VERSION 5.7 ;
  NOWIREEXTENSIONATPIN ON ;
  DIVIDERCHAR "/" ;
  BUSBITCHARS "[]" ;
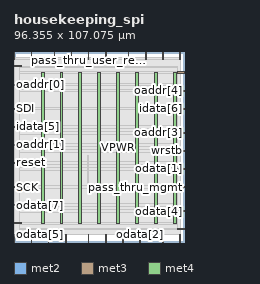
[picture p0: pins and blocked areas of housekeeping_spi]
MACRO housekeeping_spi
  CLASS BLOCK ;
  FOREIGN housekeeping_spi ;
  ORIGIN 0.000 0.000 ;
  SIZE 96.355 BY 107.075 ;
  PIN CSB
    DIRECTION INPUT ;
    USE SIGNAL ;
    ANTENNAGATEAREA 0.196500 ;
    PORT
      LAYER met2 ;
        RECT 51.610 0.000 51.890 4.000 ;
    END
  END CSB
  PIN SCK
    DIRECTION INPUT ;
    USE SIGNAL ;
    ANTENNAGATEAREA 0.852000 ;
    PORT
      LAYER met3 ;
        RECT 0.000 30.640 4.000 31.240 ;
    END
  END SCK
  PIN SDI
    DIRECTION INPUT ;
    USE SIGNAL ;
    ANTENNAGATEAREA 0.159000 ;
    PORT
      LAYER met3 ;
        RECT 0.000 74.840 4.000 75.440 ;
    END
  END SDI
  PIN SDO
    DIRECTION OUTPUT TRISTATE ;
    USE SIGNAL ;
    ANTENNADIFFAREA 0.795200 ;
    PORT
      LAYER met2 ;
        RECT 74.150 103.075 74.430 107.075 ;
    END
  END SDO
  PIN VGND
    DIRECTION INOUT ;
    USE GROUND ;
    PORT
      LAYER met4 ;
        RECT 25.990 10.640 27.590 95.440 ;
    END
    PORT
      LAYER met4 ;
        RECT 47.265 10.640 48.865 95.440 ;
    END
    PORT
      LAYER met4 ;
        RECT 68.540 10.640 70.140 95.440 ;
    END
    PORT
      LAYER met4 ;
        RECT 89.815 10.640 91.415 95.440 ;
    END
  END VGND
  PIN VPWR
    DIRECTION INOUT ;
    USE POWER ;
    PORT
      LAYER met4 ;
        RECT 15.355 10.640 16.955 95.440 ;
    END
    PORT
      LAYER met4 ;
        RECT 36.630 10.640 38.230 95.440 ;
    END
    PORT
      LAYER met4 ;
        RECT 57.905 10.640 59.505 95.440 ;
    END
    PORT
      LAYER met4 ;
        RECT 79.180 10.640 80.780 95.440 ;
    END
  END VPWR
  PIN idata[0]
    DIRECTION INPUT ;
    USE SIGNAL ;
    ANTENNAGATEAREA 0.196500 ;
    PORT
      LAYER met2 ;
        RECT 51.610 103.075 51.890 107.075 ;
    END
  END idata[0]
  PIN idata[1]
    DIRECTION INPUT ;
    USE SIGNAL ;
    ANTENNAGATEAREA 0.196500 ;
    PORT
      LAYER met2 ;
        RECT 64.490 103.075 64.770 107.075 ;
    END
  END idata[1]
  PIN idata[2]
    DIRECTION INPUT ;
    USE SIGNAL ;
    ANTENNAGATEAREA 0.196500 ;
    PORT
      LAYER met2 ;
        RECT 9.750 103.075 10.030 107.075 ;
    END
  END idata[2]
  PIN idata[3]
    DIRECTION INPUT ;
    USE SIGNAL ;
    ANTENNAGATEAREA 0.196500 ;
    PORT
      LAYER met2 ;
        RECT 93.470 0.000 93.750 4.000 ;
    END
  END idata[3]
  PIN idata[4]
    DIRECTION INPUT ;
    USE SIGNAL ;
    ANTENNAGATEAREA 0.196500 ;
    PORT
      LAYER met2 ;
        RECT 83.810 0.000 84.090 4.000 ;
    END
  END idata[4]
  PIN idata[5]
    DIRECTION INPUT ;
    USE SIGNAL ;
    ANTENNAGATEAREA 0.196500 ;
    PORT
      LAYER met3 ;
        RECT 0.000 64.640 4.000 65.240 ;
    END
  END idata[5]
  PIN idata[6]
    DIRECTION INPUT ;
    USE SIGNAL ;
    ANTENNAGATEAREA 0.196500 ;
    PORT
      LAYER met3 ;
        RECT 92.355 74.840 96.355 75.440 ;
    END
  END idata[6]
  PIN idata[7]
    DIRECTION INPUT ;
    USE SIGNAL ;
    ANTENNAGATEAREA 0.196500 ;
    PORT
      LAYER met2 ;
        RECT 22.630 103.075 22.910 107.075 ;
    END
  END idata[7]
  PIN oaddr[0]
    DIRECTION OUTPUT TRISTATE ;
    USE SIGNAL ;
    ANTENNADIFFAREA 0.795200 ;
    PORT
      LAYER met3 ;
        RECT 0.000 88.440 4.000 89.040 ;
    END
  END oaddr[0]
  PIN oaddr[1]
    DIRECTION OUTPUT TRISTATE ;
    USE SIGNAL ;
    ANTENNADIFFAREA 0.795200 ;
    PORT
      LAYER met3 ;
        RECT 0.000 54.440 4.000 55.040 ;
    END
  END oaddr[1]
  PIN oaddr[2]
    DIRECTION OUTPUT TRISTATE ;
    USE SIGNAL ;
    ANTENNADIFFAREA 0.795200 ;
    PORT
      LAYER met3 ;
        RECT 92.355 6.840 96.355 7.440 ;
    END
  END oaddr[2]
  PIN oaddr[3]
    DIRECTION OUTPUT TRISTATE ;
    USE SIGNAL ;
    ANTENNADIFFAREA 0.795200 ;
    PORT
      LAYER met3 ;
        RECT 92.355 61.240 96.355 61.840 ;
    END
  END oaddr[3]
  PIN oaddr[4]
    DIRECTION OUTPUT TRISTATE ;
    USE SIGNAL ;
    ANTENNADIFFAREA 0.445500 ;
    PORT
      LAYER met3 ;
        RECT 92.355 85.040 96.355 85.640 ;
    END
  END oaddr[4]
  PIN oaddr[5]
    DIRECTION OUTPUT TRISTATE ;
    USE SIGNAL ;
    ANTENNADIFFAREA 0.795200 ;
    PORT
      LAYER met2 ;
        RECT 0.090 0.000 0.370 4.000 ;
    END
  END oaddr[5]
  PIN oaddr[6]
    DIRECTION OUTPUT TRISTATE ;
    USE SIGNAL ;
    ANTENNADIFFAREA 0.795200 ;
    PORT
      LAYER met2 ;
        RECT 0.090 103.075 0.370 107.075 ;
    END
  END oaddr[6]
  PIN oaddr[7]
    DIRECTION OUTPUT TRISTATE ;
    USE SIGNAL ;
    ANTENNADIFFAREA 0.795200 ;
    PORT
      LAYER met3 ;
        RECT 0.000 10.240 4.000 10.840 ;
    END
  END oaddr[7]
  PIN odata[0]
    DIRECTION OUTPUT TRISTATE ;
    USE SIGNAL ;
    ANTENNADIFFAREA 0.795200 ;
    PORT
      LAYER met2 ;
        RECT 29.070 0.000 29.350 4.000 ;
    END
  END odata[0]
  PIN odata[1]
    DIRECTION OUTPUT TRISTATE ;
    USE SIGNAL ;
    ANTENNADIFFAREA 0.795200 ;
    PORT
      LAYER met3 ;
        RECT 92.355 40.840 96.355 41.440 ;
    END
  END odata[1]
  PIN odata[2]
    DIRECTION OUTPUT TRISTATE ;
    USE SIGNAL ;
    ANTENNADIFFAREA 0.795200 ;
    PORT
      LAYER met2 ;
        RECT 70.930 0.000 71.210 4.000 ;
    END
  END odata[2]
  PIN odata[3]
    DIRECTION OUTPUT TRISTATE ;
    USE SIGNAL ;
    ANTENNADIFFAREA 0.795200 ;
    PORT
      LAYER met2 ;
        RECT 83.810 103.075 84.090 107.075 ;
    END
  END odata[3]
  PIN odata[4]
    DIRECTION OUTPUT TRISTATE ;
    USE SIGNAL ;
    ANTENNADIFFAREA 0.445500 ;
    PORT
      LAYER met3 ;
        RECT 92.355 17.040 96.355 17.640 ;
    END
  END odata[4]
  PIN odata[5]
    DIRECTION OUTPUT TRISTATE ;
    USE SIGNAL ;
    ANTENNADIFFAREA 0.795200 ;
    PORT
      LAYER met2 ;
        RECT 9.750 0.000 10.030 4.000 ;
    END
  END odata[5]
  PIN odata[6]
    DIRECTION OUTPUT TRISTATE ;
    USE SIGNAL ;
    ANTENNADIFFAREA 0.795200 ;
    PORT
      LAYER met2 ;
        RECT 19.410 0.000 19.690 4.000 ;
    END
  END odata[6]
  PIN odata[7]
    DIRECTION OUTPUT TRISTATE ;
    USE SIGNAL ;
    ANTENNADIFFAREA 0.795200 ;
    PORT
      LAYER met3 ;
        RECT 0.000 20.440 4.000 21.040 ;
    END
  END odata[7]
  PIN pass_thru_mgmt
    DIRECTION OUTPUT TRISTATE ;
    USE SIGNAL ;
    ANTENNADIFFAREA 0.445500 ;
    PORT
      LAYER met3 ;
        RECT 92.355 30.640 96.355 31.240 ;
    END
  END pass_thru_mgmt
  PIN pass_thru_mgmt_delay
    DIRECTION OUTPUT TRISTATE ;
    USE SIGNAL ;
    ANTENNADIFFAREA 0.795200 ;
    PORT
      LAYER met2 ;
        RECT 41.950 0.000 42.230 4.000 ;
    END
  END pass_thru_mgmt_delay
  PIN pass_thru_mgmt_reset
    DIRECTION OUTPUT TRISTATE ;
    USE SIGNAL ;
    ANTENNADIFFAREA 0.445500 ;
    PORT
      LAYER met3 ;
        RECT 92.355 95.240 96.355 95.840 ;
    END
  END pass_thru_mgmt_reset
  PIN pass_thru_user
    DIRECTION OUTPUT TRISTATE ;
    USE SIGNAL ;
    ANTENNADIFFAREA 0.795200 ;
    PORT
      LAYER met2 ;
        RECT 93.470 103.075 93.750 107.075 ;
    END
  END pass_thru_user
  PIN pass_thru_user_delay
    DIRECTION OUTPUT TRISTATE ;
    USE SIGNAL ;
    ANTENNADIFFAREA 0.795200 ;
    PORT
      LAYER met2 ;
        RECT 32.290 103.075 32.570 107.075 ;
    END
  END pass_thru_user_delay
  PIN pass_thru_user_reset
    DIRECTION OUTPUT TRISTATE ;
    USE SIGNAL ;
    ANTENNADIFFAREA 0.795200 ;
    PORT
      LAYER met2 ;
        RECT 41.950 103.075 42.230 107.075 ;
    END
  END pass_thru_user_reset
  PIN rdstb
    DIRECTION OUTPUT TRISTATE ;
    USE SIGNAL ;
    ANTENNADIFFAREA 0.795200 ;
    PORT
      LAYER met2 ;
        RECT 61.270 0.000 61.550 4.000 ;
    END
  END rdstb
  PIN reset
    DIRECTION INPUT ;
    USE SIGNAL ;
    ANTENNAGATEAREA 0.196500 ;
    PORT
      LAYER met3 ;
        RECT 0.000 44.240 4.000 44.840 ;
    END
  END reset
  PIN sdoenb
    DIRECTION OUTPUT TRISTATE ;
    USE SIGNAL ;
    ANTENNADIFFAREA 1.336500 ;
    PORT
      LAYER met3 ;
        RECT 0.000 98.640 4.000 99.240 ;
    END
  END sdoenb
  PIN wrstb
    DIRECTION OUTPUT TRISTATE ;
    USE SIGNAL ;
    ANTENNADIFFAREA 0.445500 ;
    PORT
      LAYER met3 ;
        RECT 92.355 51.040 96.355 51.640 ;
    END
  END wrstb
  OBS
      LAYER li1 ;
        RECT 5.520 10.795 90.620 95.285 ;
      LAYER met1 ;
        RECT 0.070 10.640 93.770 95.440 ;
      LAYER met2 ;
        RECT 0.650 102.795 9.470 103.770 ;
        RECT 10.310 102.795 22.350 103.770 ;
        RECT 23.190 102.795 32.010 103.770 ;
        RECT 32.850 102.795 41.670 103.770 ;
        RECT 42.510 102.795 51.330 103.770 ;
        RECT 52.170 102.795 64.210 103.770 ;
        RECT 65.050 102.795 73.870 103.770 ;
        RECT 74.710 102.795 83.530 103.770 ;
        RECT 84.370 102.795 93.190 103.770 ;
        RECT 0.100 4.280 93.740 102.795 ;
        RECT 0.650 4.000 9.470 4.280 ;
        RECT 10.310 4.000 19.130 4.280 ;
        RECT 19.970 4.000 28.790 4.280 ;
        RECT 29.630 4.000 41.670 4.280 ;
        RECT 42.510 4.000 51.330 4.280 ;
        RECT 52.170 4.000 60.990 4.280 ;
        RECT 61.830 4.000 70.650 4.280 ;
        RECT 71.490 4.000 83.530 4.280 ;
        RECT 84.370 4.000 93.190 4.280 ;
      LAYER met3 ;
        RECT 4.400 98.240 92.355 99.090 ;
        RECT 3.070 96.240 92.355 98.240 ;
        RECT 3.070 94.840 91.955 96.240 ;
        RECT 3.070 89.440 92.355 94.840 ;
        RECT 4.400 88.040 92.355 89.440 ;
        RECT 3.070 86.040 92.355 88.040 ;
        RECT 3.070 84.640 91.955 86.040 ;
        RECT 3.070 75.840 92.355 84.640 ;
        RECT 4.400 74.440 91.955 75.840 ;
        RECT 3.070 65.640 92.355 74.440 ;
        RECT 4.400 64.240 92.355 65.640 ;
        RECT 3.070 62.240 92.355 64.240 ;
        RECT 3.070 60.840 91.955 62.240 ;
        RECT 3.070 55.440 92.355 60.840 ;
        RECT 4.400 54.040 92.355 55.440 ;
        RECT 3.070 52.040 92.355 54.040 ;
        RECT 3.070 50.640 91.955 52.040 ;
        RECT 3.070 45.240 92.355 50.640 ;
        RECT 4.400 43.840 92.355 45.240 ;
        RECT 3.070 41.840 92.355 43.840 ;
        RECT 3.070 40.440 91.955 41.840 ;
        RECT 3.070 31.640 92.355 40.440 ;
        RECT 4.400 30.240 91.955 31.640 ;
        RECT 3.070 21.440 92.355 30.240 ;
        RECT 4.400 20.040 92.355 21.440 ;
        RECT 3.070 18.040 92.355 20.040 ;
        RECT 3.070 16.640 91.955 18.040 ;
        RECT 3.070 11.240 92.355 16.640 ;
        RECT 4.400 9.840 92.355 11.240 ;
        RECT 3.070 7.840 92.355 9.840 ;
        RECT 3.070 6.975 91.955 7.840 ;
      LAYER met4 ;
        RECT 41.695 30.775 42.025 48.785 ;
  END
END housekeeping_spi
END LIBRARY

